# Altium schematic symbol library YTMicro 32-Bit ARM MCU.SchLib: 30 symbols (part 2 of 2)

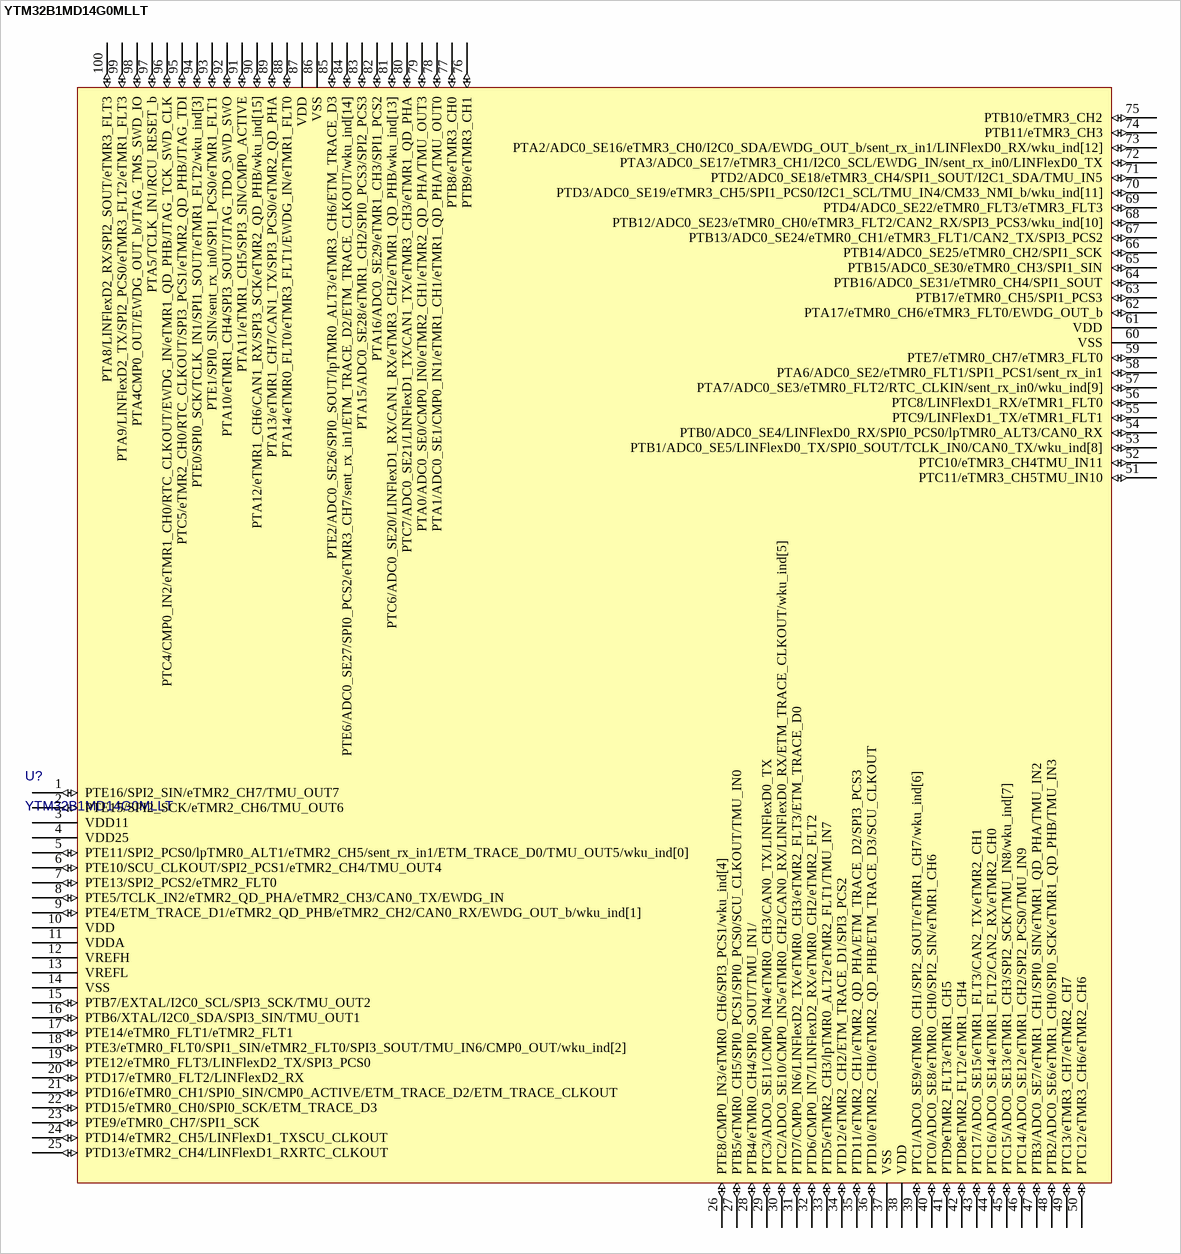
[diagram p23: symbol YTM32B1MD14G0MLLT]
## YTM32B1MD14G0MLLT
designator U?
B1M family  32-bit ARM Cortex-M33 MCU with 512K pflash and 64K SRAM, LQFP-100 package
footprint LQFP100 14x14_L
footprint LQFP100 14x14_M
footprint LQFP100 14x14_N
pins: 1 PTE16/SPI2_SIN/eTMR2_CH7/TMU_OUT7 (io), 2 PTE15/SPI2_SCK/eTMR2_CH6/TMU_OUT6 (io), 3 VDD11, 4 VDD25, 5 PTE11/SPI2_PCS0/lpTMR0_ALT1/eTMR2_CH5/sent_rx_in1/ETM_TRACE_D0/TMU_OUT5/wku_ind[0] (io), 6 PTE10/SCU_CLKOUT/SPI2_PCS1/eTMR2_CH4/TMU_OUT4 (io), 7 PTE13/SPI2_PCS2/eTMR2_FLT0 (io), 8 PTE5/TCLK_IN2/eTMR2_QD_PHA/eTMR2_CH3/CAN0_TX/EWDG_IN (io), 9 PTE4/ETM_TRACE_D1/eTMR2_QD_PHB/eTMR2_CH2/CAN0_RX/EWDG_OUT_b/wku_ind[1] (io), 10 VDD, 11 VDDA, 12 VREFH, 13 VREFL, 14 VSS, 15 PTB7/EXTAL/I2C0_SCL/SPI3_SCK/TMU_OUT2 (io), 16 PTB6/XTAL/I2C0_SDA/SPI3_SIN/TMU_OUT1 (io), 17 PTE14/eTMR0_FLT1/eTMR2_FLT1 (io), 18 PTE3/eTMR0_FLT0/SPI1_SIN/eTMR2_FLT0/SPI3_SOUT/TMU_IN6/CMP0_OUT/wku_ind[2] (io), 19 PTE12/eTMR0_FLT3/LINFlexD2_TX/SPI3_PCS0 (io), 20 PTD17/eTMR0_FLT2/LINFlexD2_RX (io), 21 PTD16/eTMR0_CH1/SPI0_SIN/CMP0_ACTIVE/ETM_TRACE_D2/ETM_TRACE_CLKOUT (io), 22 PTD15/eTMR0_CH0/SPI0_SCK/ETM_TRACE_D3 (io), 23 PTE9/eTMR0_CH7/SPI1_SCK (io), 24 PTD14/eTMR2_CH5/LINFlexD1_TXSCU_CLKOUT (io), 25 PTD13/eTMR2_CH4/LINFlexD1_RXRTC_CLKOUT (io), 26 PTE8/CMP0_IN3/eTMR0_CH6/SPI3_PCS1/wku_ind[4] (io), 27 PTB5/eTMR0_CH5/SPI0_PCS1/SPI0_PCS0/SCU_CLKOUT/TMU_IN0 (io), 28 PTB4/eTMR0_CH4/SPI0_SOUT/TMU_IN1/ (io), 29 PTC3/ADC0_SE11/CMP0_IN4/eTMR0_CH3/CAN0_TX/LINFlexD0_TX (io), 30 PTC2/ADC0_SE10/CMP0_IN5/eTMR0_CH2/CAN0_RX/LINFlexD0_RX/ETM_TRACE_CLKOUT/wku_ind[5] (io), 31 PTD7/CMP0_IN6/LINFlexD2_TX/eTMR0_CH3/eTMR2_FLT3/ETM_TRACE_D0 (io), 32 PTD6/CMP0_IN7/LINFlexD2_RX/eTMR0_CH2/eTMR2_FLT2 (io), 33 PTD5/eTMR2_CH3/lpTMR0_ALT2/eTMR2_FLT1/TMU_IN7 (io), 34 PTD12/eTMR2_CH2/ETM_TRACE_D1/SPI3_PCS2 (io), 35 PTD11/eTMR2_CH1/eTMR2_QD_PHA/ETM_TRACE_D2/SPI3_PCS3 (io), 36 PTD10/eTMR2_CH0/eTMR2_QD_PHB/ETM_TRACE_D3/SCU_CLKOUT (io), 37 VSS, 38 VDD, 39 PTC1/ADC0_SE9/eTMR0_CH1/SPI2_SOUT/eTMR1_CH7/wku_ind[6] (io), 40 PTC0/ADC0_SE8/eTMR0_CH0/SPI2_SIN/eTMR1_CH6 (io), 41 PTD9eTMR2_FLT3/eTMR1_CH5 (io), 42 PTD8eTMR2_FLT2/eTMR1_CH4 (io), 43 PTC17/ADC0_SE15/eTMR1_FLT3/CAN2_TX/eTMR2_CH1 (io), 44 PTC16/ADC0_SE14/eTMR1_FLT2/CAN2_RX/eTMR2_CH0 (io), 45 PTC15/ADC0_SE13/eTMR1_CH3/SPI2_SCK/TMU_IN8/wku_ind[7] (io), 46 PTC14/ADC0_SE12/eTMR1_CH2/SPI2_PCS0/TMU_IN9 (io), 47 PTB3/ADC0_SE7/eTMR1_CH1/SPI0_SIN/eTMR1_QD_PHA/TMU_IN2 (io), 48 PTB2/ADC0_SE6/eTMR1_CH0/SPI0_SCK/eTMR1_QD_PHB/TMU_IN3 (io), 49 PTC13/eTMR3_CH7/eTMR2_CH7 (io), 50 PTC12/eTMR3_CH6/eTMR2_CH6 (io), 51 PTC11/eTMR3_CH5TMU_IN10 (io), 52 PTC10/eTMR3_CH4TMU_IN11 (io), 53 PTB1/ADC0_SE5/LINFlexD0_TX/SPI0_SOUT/TCLK_IN0/CAN0_TX/wku_ind[8] (io), 54 PTB0/ADC0_SE4/LINFlexD0_RX/SPI0_PCS0/lpTMR0_ALT3/CAN0_RX (io), 55 PTC9/LINFlexD1_TX/eTMR1_FLT1 (io), 56 PTC8/LINFlexD1_RX/eTMR1_FLT0 (io), 57 PTA7/ADC0_SE3/eTMR0_FLT2/RTC_CLKIN/sent_rx_in0/wku_ind[9] (io), 58 PTA6/ADC0_SE2/eTMR0_FLT1/SPI1_PCS1/sent_rx_in1 (io), 59 PTE7/eTMR0_CH7/eTMR3_FLT0 (io), 60 VSS, 61 VDD, 62 PTA17/eTMR0_CH6/eTMR3_FLT0/EWDG_OUT_b (io), 63 PTB17/eTMR0_CH5/SPI1_PCS3 (io), 64 PTB16/ADC0_SE31/eTMR0_CH4/SPI1_SOUT (io), 65 PTB15/ADC0_SE30/eTMR0_CH3/SPI1_SIN (io), 66 PTB14/ADC0_SE25/eTMR0_CH2/SPI1_SCK (io), 67 PTB13/ADC0_SE24/eTMR0_CH1/eTMR3_FLT1/CAN2_TX/SPI3_PCS2 (io), 68 PTB12/ADC0_SE23/eTMR0_CH0/eTMR3_FLT2/CAN2_RX/SPI3_PCS3/wku_ind[10] (io), 69 PTD4/ADC0_SE22/eTMR0_FLT3/eTMR3_FLT3 (io), 70 PTD3/ADC0_SE19/eTMR3_CH5/SPI1_PCS0/I2C1_SCL/TMU_IN4/CM33_NMI_b/wku_ind[11] (io), 71 PTD2/ADC0_SE18/eTMR3_CH4/SPI1_SOUT/I2C1_SDA/TMU_IN5 (io), 72 PTA3/ADC0_SE17/eTMR3_CH1/I2C0_SCL/EWDG_IN/sent_rx_in0/LINFlexD0_TX (io), 73 PTA2/ADC0_SE16/eTMR3_CH0/I2C0_SDA/EWDG_OUT_b/sent_rx_in1/LINFlexD0_RX/wku_ind[12] (io), 74 PTB11/eTMR3_CH3 (io), 75 PTB10/eTMR3_CH2 (io), 76 PTB9/eTMR3_CH1 (io), 77 PTB8/eTMR3_CH0 (io), 78 PTA1/ADC0_SE1/CMP0_IN1/eTMR1_CH1/eTMR1_QD_PHA/TMU_OUT0 (io), 79 PTA0/ADC0_SE0/CMP0_IN0/eTMR2_CH1/eTMR2_QD_PHA/TMU_OUT3 (io), 80 PTC7/ADC0_SE21/LINFlexD1_TX/CAN1_TX/eTMR3_CH3/eTMR1_QD_PHA (io), 81 PTC6/ADC0_SE20/LINFlexD1_RX/CAN1_RX/eTMR3_CH2/eTMR1_QD_PHB/wku_ind[13] (io), 82 PTA16/ADC0_SE29/eTMR1_CH3/SPI1_PCS2 (io), 83 PTA15/ADC0_SE28/eTMR1_CH2/SPI0_PCS3/SPI2_PCS3 (io), 84 PTE6/ADC0_SE27/SPI0_PCS2/eTMR3_CH7/sent_rx_in1/ETM_TRACE_D2/ETM_TRACE_CLKOUT/wku_ind[14] (io), 85 PTE2/ADC0_SE26/SPI0_SOUT/lpTMR0_ALT3/eTMR3_CH6/ETM_TRACE_D3 (io), 86 VSS, 87 VDD, 88 PTA14/eTMR0_FLT0/eTMR3_FLT1/EWDG_IN/eTMR1_FLT0 (io), 89 PTA13/eTMR1_CH7/CAN1_TX/SPI3_PCS0/eTMR2_QD_PHA (io), 90 PTA12/eTMR1_CH6/CAN1_RX/SPI3_SCK/eTMR2_QD_PHB/wku_ind[15] (io), 91 PTA11/eTMR1_CH5/SPI3_SIN/CMP0_ACTIVE (io), 92 PTA10/eTMR1_CH4/SPI3_SOUT/JTAG_TDO_SWD_SWO (io), 93 PTE1/SPI0_SIN/sent_rx_in0/SPI1_PCS0/eTMR1_FLT1 (io), 94 PTE0/SPI0_SCK/TCLK_IN1/SPI1_SOUT/eTMR1_FLT2/wku_ind[3] (io), 95 PTC5/eTMR2_CH0/RTC_CLKOUT/SPI3_PCS1/eTMR2_QD_PHB/JTAG_TDI (io), 96 PTC4/CMP0_IN2/eTMR1_CH0/RTC_CLKOUT/EWDG_IN/eTMR1_QD_PHB/JTAG_TCK_SWD_CLK (io), 97 PTA5/TCLK_IN1/RCU_RESET_b (io), 98 PTA4CMP0_OUT/EWDG_OUT_b/JTAG_TMS_SWD_IO (io), 99 PTA9/LINFlexD2_TX/SPI2_PCS0/eTMR3_FLT2/eTMR1_FLT3 (io), 100 PTA8/LINFlexD2_RX/SPI2_SOUT/eTMR3_FLT3 (io)


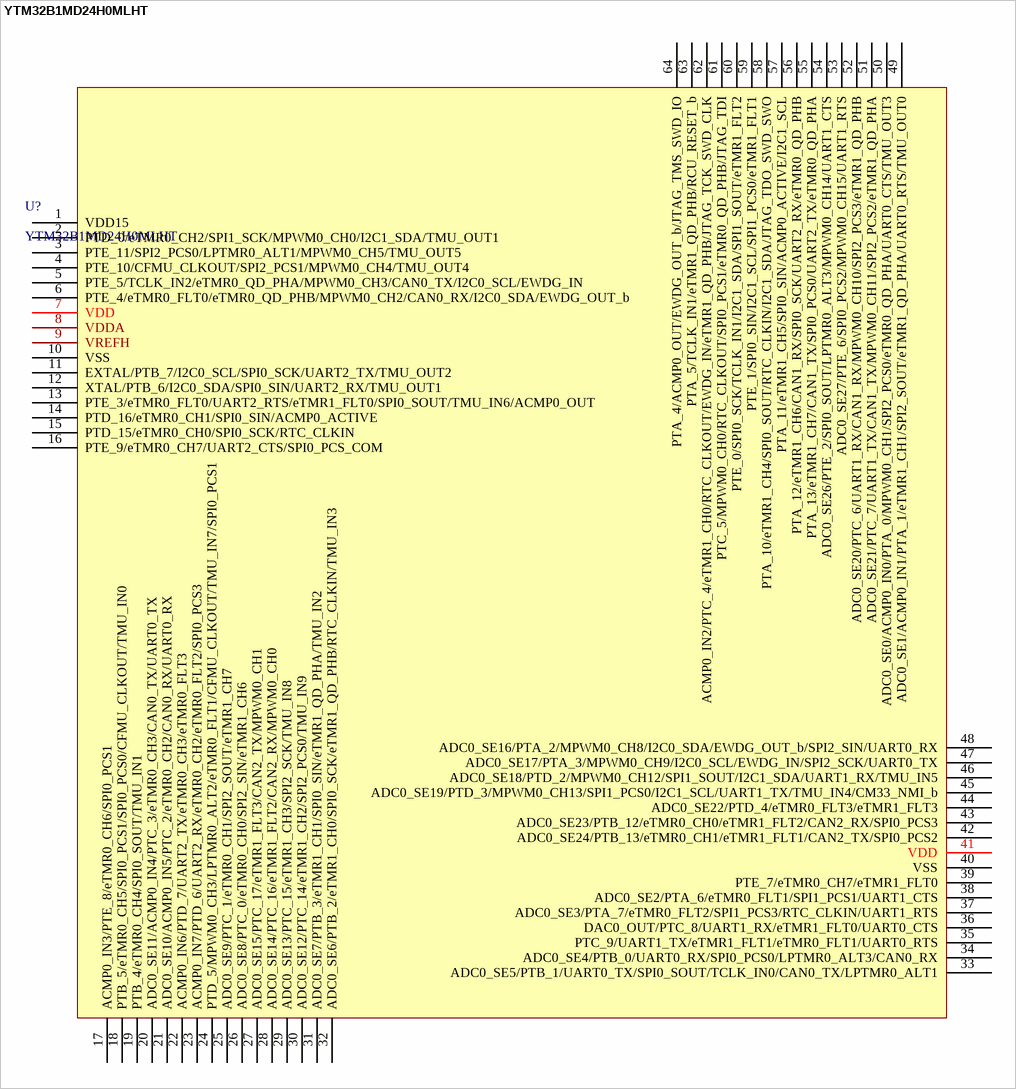
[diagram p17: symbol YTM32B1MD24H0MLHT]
## YTM32B1MD24H0MLHT
designator U?
B1M family  32-bit ARM Cortex-M33 MCU with 512K pflash and 64K SRAM, LQFP-64 package
footprint LQFP64 10x10_M
pins: 1 VDD15, 2 PTD_0/eTMR0_CH2/SPI1_SCK/MPWM0_CH0/I2C1_SDA/TMU_OUT1, 3 PTE_11/SPI2_PCS0/LPTMR0_ALT1/MPWM0_CH5/TMU_OUT5, 4 PTE_10/CFMU_CLKOUT/SPI2_PCS1/MPWM0_CH4/TMU_OUT4, 5 PTE_5/TCLK_IN2/eTMR0_QD_PHA/MPWM0_CH3/CAN0_TX/I2C0_SCL/EWDG_IN, 6 PTE_4/eTMR0_FLT0/eTMR0_QD_PHB/MPWM0_CH2/CAN0_RX/I2C0_SDA/EWDG_OUT_b, 7 VDD, 8 VDDA, 9 VREFH, 10 VSS, 11 EXTAL/PTB_7/I2C0_SCL/SPI0_SCK/UART2_TX/TMU_OUT2, 12 XTAL/PTB_6/I2C0_SDA/SPI0_SIN/UART2_RX/TMU_OUT1, 13 PTE_3/eTMR0_FLT0/UART2_RTS/eTMR1_FLT0/SPI0_SOUT/TMU_IN6/ACMP0_OUT, 14 PTD_16/eTMR0_CH1/SPI0_SIN/ACMP0_ACTIVE, 15 PTD_15/eTMR0_CH0/SPI0_SCK/RTC_CLKIN, 16 PTE_9/eTMR0_CH7/UART2_CTS/SPI0_PCS_COM, 17 ACMP0_IN3/PTE_8/eTMR0_CH6/SPI0_PCS1, 18 PTB_5/eTMR0_CH5/SPI0_PCS1/SPI0_PCS0/CFMU_CLKOUT/TMU_IN0, 19 PTB_4/eTMR0_CH4/SPI0_SOUT/TMU_IN1, 20 ADC0_SE11/ACMP0_IN4/PTC_3/eTMR0_CH3/CAN0_TX/UART0_TX, 21 ADC0_SE10/ACMP0_IN5/PTC_2/eTMR0_CH2/CAN0_RX/UART0_RX, 22 ACMP0_IN6/PTD_7/UART2_TX/eTMR0_CH3/eTMR0_FLT3, 23 ACMP0_IN7/PTD_6/UART2_RX/eTMR0_CH2/eTMR0_FLT2/SPI0_PCS3, 24 PTD_5/MPWM0_CH3/LPTMR0_ALT2/eTMR0_FLT1/CFMU_CLKOUT/TMU_IN7/SPI0_PCS1, 25 ADC0_SE9/PTC_1/eTMR0_CH1/SPI2_SOUT/eTMR1_CH7, 26 ADC0_SE8/PTC_0/eTMR0_CH0/SPI2_SIN/eTMR1_CH6, 27 ADC0_SE15/PTC_17/eTMR1_FLT3/CAN2_TX/MPWM0_CH1, 28 ADC0_SE14/PTC_16/eTMR1_FLT2/CAN2_RX/MPWM0_CH0, 29 ADC0_SE13/PTC_15/eTMR1_CH3/SPI2_SCK/TMU_IN8, 30 ADC0_SE12/PTC_14/eTMR1_CH2/SPI2_PCS0/TMU_IN9, 31 ADC0_SE7/PTB_3/eTMR1_CH1/SPI0_SIN/eTMR1_QD_PHA/TMU_IN2, 32 ADC0_SE6/PTB_2/eTMR1_CH0/SPI0_SCK/eTMR1_QD_PHB/RTC_CLKIN/TMU_IN3, 33 ADC0_SE5/PTB_1/UART0_TX/SPI0_SOUT/TCLK_IN0/CAN0_TX/LPTMR0_ALT1, 34 ADC0_SE4/PTB_0/UART0_RX/SPI0_PCS0/LPTMR0_ALT3/CAN0_RX, 35 PTC_9/UART1_TX/eTMR1_FLT1/eTMR0_FLT1/UART0_RTS, 36 DAC0_OUT/PTC_8/UART1_RX/eTMR1_FLT0/UART0_CTS, 37 ADC0_SE3/PTA_7/eTMR0_FLT2/SPI1_PCS3/RTC_CLKIN/UART1_RTS, 38 ADC0_SE2/PTA_6/eTMR0_FLT1/SPI1_PCS1/UART1_CTS, 39 PTE_7/eTMR0_CH7/eTMR1_FLT0, 40 VSS, 41 VDD, 42 ADC0_SE24/PTB_13/eTMR0_CH1/eTMR1_FLT1/CAN2_TX/SPI0_PCS2, 43 ADC0_SE23/PTB_12/eTMR0_CH0/eTMR1_FLT2/CAN2_RX/SPI0_PCS3, 44 ADC0_SE22/PTD_4/eTMR0_FLT3/eTMR1_FLT3, 45 ADC0_SE19/PTD_3/MPWM0_CH13/SPI1_PCS0/I2C1_SCL/UART1_TX/TMU_IN4/CM33_NMI_b, 46 ADC0_SE18/PTD_2/MPWM0_CH12/SPI1_SOUT/I2C1_SDA/UART1_RX/TMU_IN5, 47 ADC0_SE17/PTA_3/MPWM0_CH9/I2C0_SCL/EWDG_IN/SPI2_SCK/UART0_TX, 48 ADC0_SE16/PTA_2/MPWM0_CH8/I2C0_SDA/EWDG_OUT_b/SPI2_SIN/UART0_RX, 49 ADC0_SE1/ACMP0_IN1/PTA_1/eTMR1_CH1/SPI2_SOUT/eTMR1_QD_PHA/UART0_RTS/TMU_OUT0, 50 ADC0_SE0/ACMP0_IN0/PTA_0/MPWM0_CH1/SPI2_PCS0/eTMR0_QD_PHA/UART0_CTS/TMU_OUT3, 51 ADC0_SE21/PTC_7/UART1_TX/CAN1_TX/MPWM0_CH11/SPI2_PCS2/eTMR1_QD_PHA, 52 ADC0_SE20/PTC_6/UART1_RX/CAN1_RX/MPWM0_CH10/SPI2_PCS3/eTMR1_QD_PHB, 53 ADC0_SE27/PTE_6/SPI0_PCS2/MPWM0_CH15/UART1_RTS, 54 ADC0_SE26/PTE_2/SPI0_SOUT/LPTMR0_ALT3/MPWM0_CH14/UART1_CTS, 55 PTA_13/eTMR1_CH7/CAN1_TX/SPI0_PCS0/UART2_TX/eTMR0_QD_PHA, 56 PTA_12/eTMR1_CH6/CAN1_RX/SPI0_SCK/UART2_RX/eTMR0_QD_PHB, 57 PTA_11/eTMR1_CH5/SPI0_SIN/ACMP0_ACTIVE/I2C1_SCL, 58 PTA_10/eTMR1_CH4/SPI0_SOUT/RTC_CLKIN/I2C1_SDA/JTAG_TDO_SWD_SWO, 59 PTE_1/SPI0_SIN/I2C1_SCL/SPI1_PCS0/eTMR1_FLT1, 60 PTE_0/SPI0_SCK/TCLK_IN1/I2C1_SDA/SPI1_SOUT/eTMR1_FLT2, 61 PTC_5/MPWM0_CH0/RTC_CLKOUT/SPI0_PCS1/eTMR0_QD_PHB/JTAG_TDI, 62 ACMP0_IN2/PTC_4/eTMR1_CH0/RTC_CLKOUT/EWDG_IN/eTMR1_QD_PHB/JTAG_TCK_SWD_CLK, 63 PTA_5/TCLK_IN1/eTMR1_QD_PHB/RCU_RESET_b, 64 PTA_4/ACMP0_OUT/EWDG_OUT_b/JTAG_TMS_SWD_IO


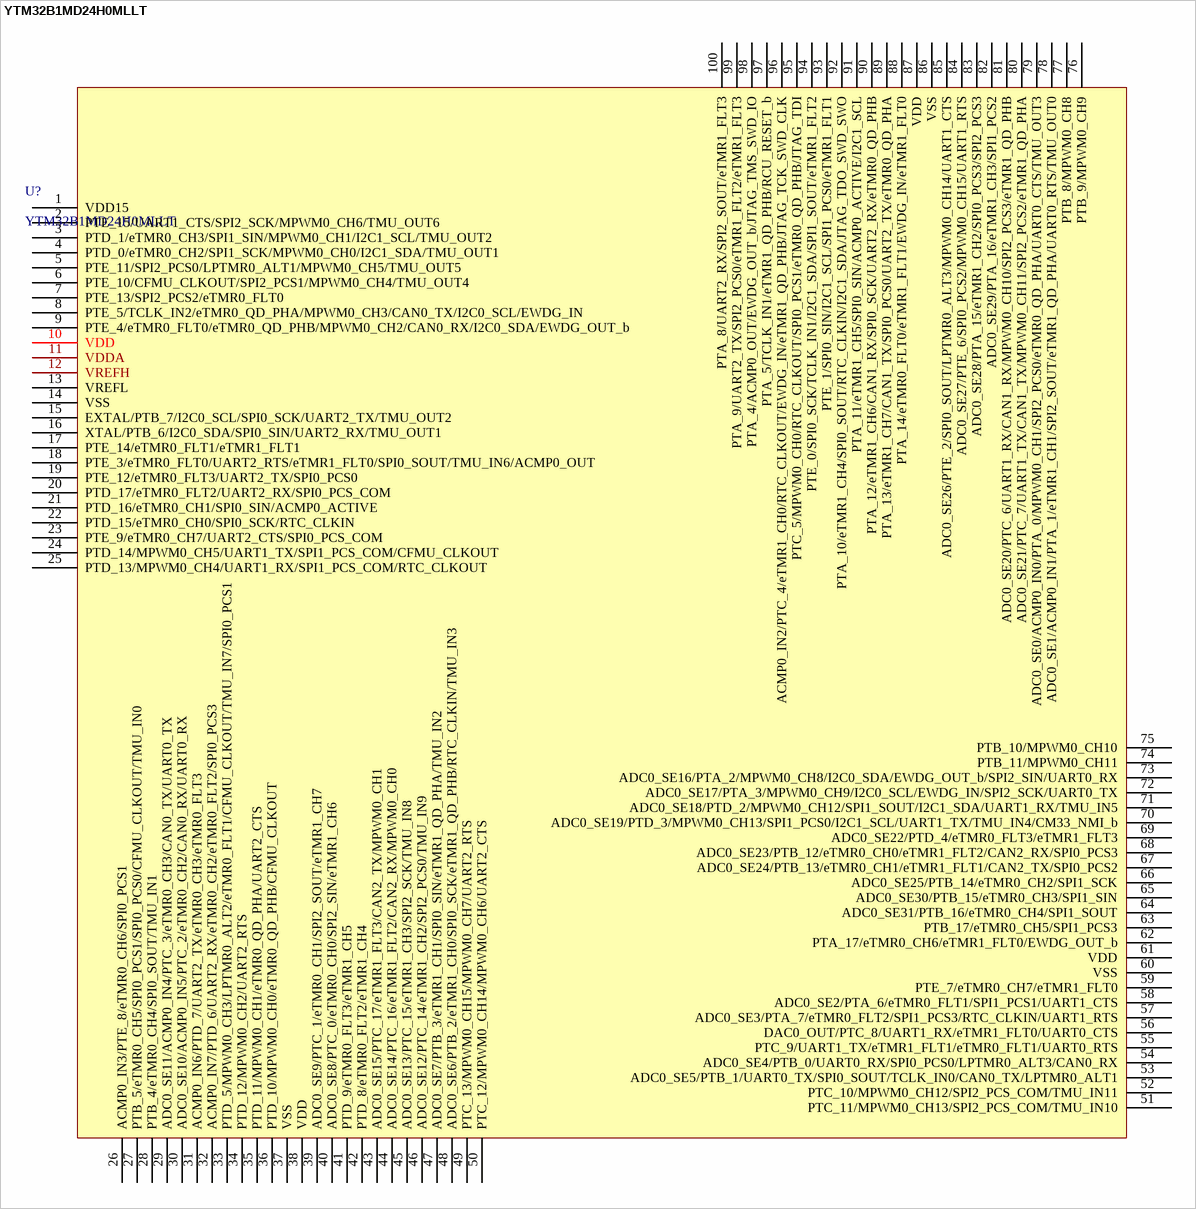
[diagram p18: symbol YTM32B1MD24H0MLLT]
## YTM32B1MD24H0MLLT
designator U?
B1M family  32-bit ARM Cortex-M33 MCU with 512K pflash and 64K SRAM, LQFP-100 package
footprint LQFP100 14x14_M
pins: 1 VDD15, 2 PTE_15/UART1_CTS/SPI2_SCK/MPWM0_CH6/TMU_OUT6, 3 PTD_1/eTMR0_CH3/SPI1_SIN/MPWM0_CH1/I2C1_SCL/TMU_OUT2, 4 PTD_0/eTMR0_CH2/SPI1_SCK/MPWM0_CH0/I2C1_SDA/TMU_OUT1, 5 PTE_11/SPI2_PCS0/LPTMR0_ALT1/MPWM0_CH5/TMU_OUT5, 6 PTE_10/CFMU_CLKOUT/SPI2_PCS1/MPWM0_CH4/TMU_OUT4, 7 PTE_13/SPI2_PCS2/eTMR0_FLT0, 8 PTE_5/TCLK_IN2/eTMR0_QD_PHA/MPWM0_CH3/CAN0_TX/I2C0_SCL/EWDG_IN, 9 PTE_4/eTMR0_FLT0/eTMR0_QD_PHB/MPWM0_CH2/CAN0_RX/I2C0_SDA/EWDG_OUT_b, 10 VDD, 11 VDDA, 12 VREFH, 13 VREFL, 14 VSS, 15 EXTAL/PTB_7/I2C0_SCL/SPI0_SCK/UART2_TX/TMU_OUT2, 16 XTAL/PTB_6/I2C0_SDA/SPI0_SIN/UART2_RX/TMU_OUT1, 17 PTE_14/eTMR0_FLT1/eTMR1_FLT1, 18 PTE_3/eTMR0_FLT0/UART2_RTS/eTMR1_FLT0/SPI0_SOUT/TMU_IN6/ACMP0_OUT, 19 PTE_12/eTMR0_FLT3/UART2_TX/SPI0_PCS0, 20 PTD_17/eTMR0_FLT2/UART2_RX/SPI0_PCS_COM, 21 PTD_16/eTMR0_CH1/SPI0_SIN/ACMP0_ACTIVE, 22 PTD_15/eTMR0_CH0/SPI0_SCK/RTC_CLKIN, 23 PTE_9/eTMR0_CH7/UART2_CTS/SPI0_PCS_COM, 24 PTD_14/MPWM0_CH5/UART1_TX/SPI1_PCS_COM/CFMU_CLKOUT, 25 PTD_13/MPWM0_CH4/UART1_RX/SPI1_PCS_COM/RTC_CLKOUT, 26 ACMP0_IN3/PTE_8/eTMR0_CH6/SPI0_PCS1, 27 PTB_5/eTMR0_CH5/SPI0_PCS1/SPI0_PCS0/CFMU_CLKOUT/TMU_IN0, 28 PTB_4/eTMR0_CH4/SPI0_SOUT/TMU_IN1, 29 ADC0_SE11/ACMP0_IN4/PTC_3/eTMR0_CH3/CAN0_TX/UART0_TX, 30 ADC0_SE10/ACMP0_IN5/PTC_2/eTMR0_CH2/CAN0_RX/UART0_RX, 31 ACMP0_IN6/PTD_7/UART2_TX/eTMR0_CH3/eTMR0_FLT3, 32 ACMP0_IN7/PTD_6/UART2_RX/eTMR0_CH2/eTMR0_FLT2/SPI0_PCS3, 33 PTD_5/MPWM0_CH3/LPTMR0_ALT2/eTMR0_FLT1/CFMU_CLKOUT/TMU_IN7/SPI0_PCS1, 34 PTD_12/MPWM0_CH2/UART2_RTS, 35 PTD_11/MPWM0_CH1/eTMR0_QD_PHA/UART2_CTS, 36 PTD_10/MPWM0_CH0/eTMR0_QD_PHB/CFMU_CLKOUT, 37 VSS, 38 VDD, 39 ADC0_SE9/PTC_1/eTMR0_CH1/SPI2_SOUT/eTMR1_CH7, 40 ADC0_SE8/PTC_0/eTMR0_CH0/SPI2_SIN/eTMR1_CH6, 41 PTD_9/eTMR0_FLT3/eTMR1_CH5, 42 PTD_8/eTMR0_FLT2/eTMR1_CH4, 43 ADC0_SE15/PTC_17/eTMR1_FLT3/CAN2_TX/MPWM0_CH1, 44 ADC0_SE14/PTC_16/eTMR1_FLT2/CAN2_RX/MPWM0_CH0, 45 ADC0_SE13/PTC_15/eTMR1_CH3/SPI2_SCK/TMU_IN8, 46 ADC0_SE12/PTC_14/eTMR1_CH2/SPI2_PCS0/TMU_IN9, 47 ADC0_SE7/PTB_3/eTMR1_CH1/SPI0_SIN/eTMR1_QD_PHA/TMU_IN2, 48 ADC0_SE6/PTB_2/eTMR1_CH0/SPI0_SCK/eTMR1_QD_PHB/RTC_CLKIN/TMU_IN3, 49 PTC_13/MPWM0_CH15/MPWM0_CH7/UART2_RTS, 50 PTC_12/MPWM0_CH14/MPWM0_CH6/UART2_CTS, 51 PTC_11/MPWM0_CH13/SPI2_PCS_COM/TMU_IN10, 52 PTC_10/MPWM0_CH12/SPI2_PCS_COM/TMU_IN11, 53 ADC0_SE5/PTB_1/UART0_TX/SPI0_SOUT/TCLK_IN0/CAN0_TX/LPTMR0_ALT1, 54 ADC0_SE4/PTB_0/UART0_RX/SPI0_PCS0/LPTMR0_ALT3/CAN0_RX, 55 PTC_9/UART1_TX/eTMR1_FLT1/eTMR0_FLT1/UART0_RTS, 56 DAC0_OUT/PTC_8/UART1_RX/eTMR1_FLT0/UART0_CTS, 57 ADC0_SE3/PTA_7/eTMR0_FLT2/SPI1_PCS3/RTC_CLKIN/UART1_RTS, 58 ADC0_SE2/PTA_6/eTMR0_FLT1/SPI1_PCS1/UART1_CTS, 59 PTE_7/eTMR0_CH7/eTMR1_FLT0, 60 VSS, 61 VDD, 62 PTA_17/eTMR0_CH6/eTMR1_FLT0/EWDG_OUT_b, 63 PTB_17/eTMR0_CH5/SPI1_PCS3, 64 ADC0_SE31/PTB_16/eTMR0_CH4/SPI1_SOUT, 65 ADC0_SE30/PTB_15/eTMR0_CH3/SPI1_SIN, 66 ADC0_SE25/PTB_14/eTMR0_CH2/SPI1_SCK, 67 ADC0_SE24/PTB_13/eTMR0_CH1/eTMR1_FLT1/CAN2_TX/SPI0_PCS2, 68 ADC0_SE23/PTB_12/eTMR0_CH0/eTMR1_FLT2/CAN2_RX/SPI0_PCS3, 69 ADC0_SE22/PTD_4/eTMR0_FLT3/eTMR1_FLT3, 70 ADC0_SE19/PTD_3/MPWM0_CH13/SPI1_PCS0/I2C1_SCL/UART1_TX/TMU_IN4/CM33_NMI_b, 71 ADC0_SE18/PTD_2/MPWM0_CH12/SPI1_SOUT/I2C1_SDA/UART1_RX/TMU_IN5, 72 ADC0_SE17/PTA_3/MPWM0_CH9/I2C0_SCL/EWDG_IN/SPI2_SCK/UART0_TX, 73 ADC0_SE16/PTA_2/MPWM0_CH8/I2C0_SDA/EWDG_OUT_b/SPI2_SIN/UART0_RX, 74 PTB_11/MPWM0_CH11, 75 PTB_10/MPWM0_CH10, 76 PTB_9/MPWM0_CH9, 77 PTB_8/MPWM0_CH8, 78 ADC0_SE1/ACMP0_IN1/PTA_1/eTMR1_CH1/SPI2_SOUT/eTMR1_QD_PHA/UART0_RTS/TMU_OUT0, 79 ADC0_SE0/ACMP0_IN0/PTA_0/MPWM0_CH1/SPI2_PCS0/eTMR0_QD_PHA/UART0_CTS/TMU_OUT3, 80 ADC0_SE21/PTC_7/UART1_TX/CAN1_TX/MPWM0_CH11/SPI2_PCS2/eTMR1_QD_PHA, 81 ADC0_SE20/PTC_6/UART1_RX/CAN1_RX/MPWM0_CH10/SPI2_PCS3/eTMR1_QD_PHB, 82 ADC0_SE29/PTA_16/eTMR1_CH3/SPI1_PCS2, 83 ADC0_SE28/PTA_15/eTMR1_CH2/SPI0_PCS3/SPI2_PCS3, 84 ADC0_SE27/PTE_6/SPI0_PCS2/MPWM0_CH15/UART1_RTS, 85 ADC0_SE26/PTE_2/SPI0_SOUT/LPTMR0_ALT3/MPWM0_CH14/UART1_CTS, 86 VSS, 87 VDD, 88 PTA_14/eTMR0_FLT0/eTMR1_FLT1/EWDG_IN/eTMR1_FLT0, 89 PTA_13/eTMR1_CH7/CAN1_TX/SPI0_PCS0/UART2_TX/eTMR0_QD_PHA, 90 PTA_12/eTMR1_CH6/CAN1_RX/SPI0_SCK/UART2_RX/eTMR0_QD_PHB, 91 PTA_11/eTMR1_CH5/SPI0_SIN/ACMP0_ACTIVE/I2C1_SCL, 92 PTA_10/eTMR1_CH4/SPI0_SOUT/RTC_CLKIN/I2C1_SDA/JTAG_TDO_SWD_SWO, 93 PTE_1/SPI0_SIN/I2C1_SCL/SPI1_PCS0/eTMR1_FLT1, 94 PTE_0/SPI0_SCK/TCLK_IN1/I2C1_SDA/SPI1_SOUT/eTMR1_FLT2, 95 PTC_5/MPWM0_CH0/RTC_CLKOUT/SPI0_PCS1/eTMR0_QD_PHB/JTAG_TDI, 96 ACMP0_IN2/PTC_4/eTMR1_CH0/RTC_CLKOUT/EWDG_IN/eTMR1_QD_PHB/JTAG_TCK_SWD_CLK, 97 PTA_5/TCLK_IN1/eTMR1_QD_PHB/RCU_RESET_b, 98 PTA_4/ACMP0_OUT/EWDG_OUT_b/JTAG_TMS_SWD_IO, 99 PTA_9/UART2_TX/SPI2_PCS0/eTMR1_FLT2/eTMR1_FLT3, 100 PTA_8/UART2_RX/SPI2_SOUT/eTMR1_FLT3


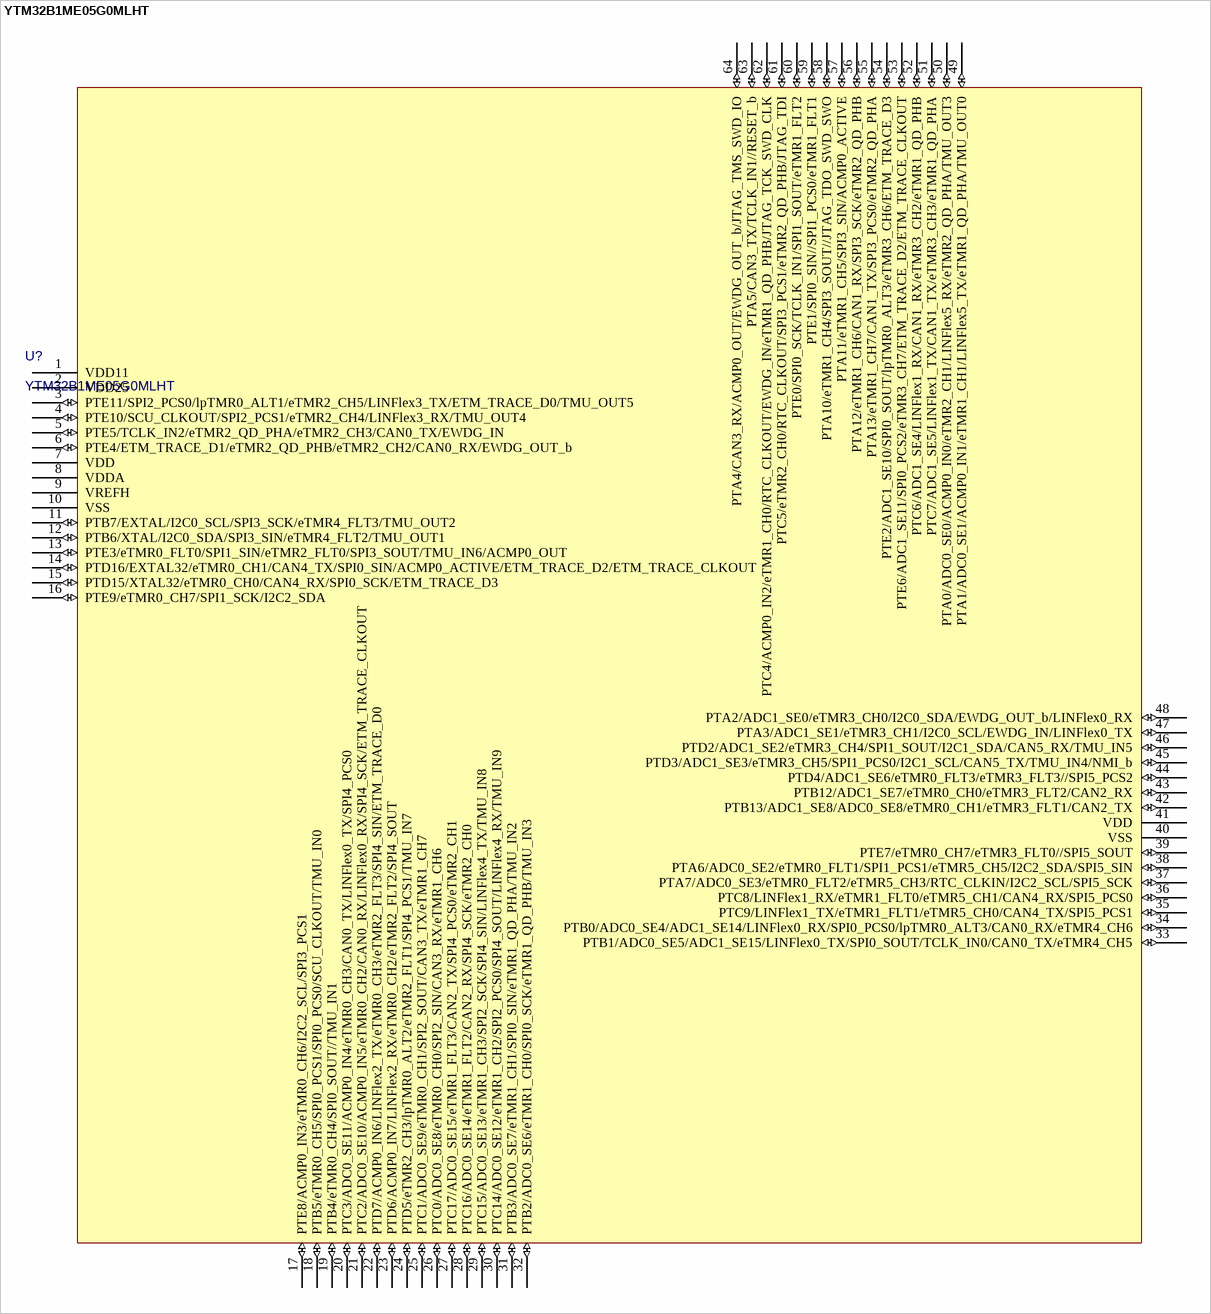
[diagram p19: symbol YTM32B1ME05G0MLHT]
## YTM32B1ME05G0MLHT
designator U?
B1M family  32-bit ARM Cortex-M33 MCU with 1M pflash, 256K dflash and 128K SRAM, LQFP-64 package
footprint LQFP64 10x10_L
footprint LQFP64 10x10_M
footprint LQFP64 10x10_N
pins: 1 VDD11, 2 VDD25, 3 PTE11/SPI2_PCS0/lpTMR0_ALT1/eTMR2_CH5/LINFlex3_TX/ETM_TRACE_D0/TMU_OUT5 (io), 4 PTE10/SCU_CLKOUT/SPI2_PCS1/eTMR2_CH4/LINFlex3_RX/TMU_OUT4 (io), 5 PTE5/TCLK_IN2/eTMR2_QD_PHA/eTMR2_CH3/CAN0_TX/EWDG_IN (io), 6 PTE4/ETM_TRACE_D1/eTMR2_QD_PHB/eTMR2_CH2/CAN0_RX/EWDG_OUT_b (io), 7 VDD, 8 VDDA, 9 VREFH, 10 VSS, 11 PTB7/EXTAL/I2C0_SCL/SPI3_SCK/eTMR4_FLT3/TMU_OUT2 (io), 12 PTB6/XTAL/I2C0_SDA/SPI3_SIN/eTMR4_FLT2/TMU_OUT1 (io), 13 PTE3/eTMR0_FLT0/SPI1_SIN/eTMR2_FLT0/SPI3_SOUT/TMU_IN6/ACMP0_OUT (io), 14 PTD16/EXTAL32/eTMR0_CH1/CAN4_TX/SPI0_SIN/ACMP0_ACTIVE/ETM_TRACE_D2/ETM_TRACE_CLKOUT (io), 15 PTD15/XTAL32/eTMR0_CH0/CAN4_RX/SPI0_SCK/ETM_TRACE_D3 (io), 16 PTE9/eTMR0_CH7/SPI1_SCK/I2C2_SDA (io), 17 PTE8/ACMP0_IN3/eTMR0_CH6/I2C2_SCL/SPI3_PCS1 (io), 18 PTB5/eTMR0_CH5/SPI0_PCS1/SPI0_PCS0/SCU_CLKOUT/TMU_IN0 (io), 19 PTB4/eTMR0_CH4/SPI0_SOUT//TMU_IN1 (io), 20 PTC3/ADC0_SE11/ACMP0_IN4/eTMR0_CH3/CAN0_TX/LINFlex0_TX/SPI4_PCS0 (io), 21 PTC2/ADC0_SE10/ACMP0_IN5/eTMR0_CH2/CAN0_RX/LINFlex0_RX/SPI4_SCK/ETM_TRACE_CLKOUT (io), 22 PTD7/ACMP0_IN6/LINFlex2_TX/eTMR0_CH3/eTMR2_FLT3/SPI4_SIN/ETM_TRACE_D0 (io), 23 PTD6/ACMP0_IN7/LINFlex2_RX/eTMR0_CH2/eTMR2_FLT2/SPI4_SOUT (io), 24 PTD5/eTMR2_CH3/lpTMR0_ALT2/eTMR2_FLT1/SPI4_PCS1/TMU_IN7 (io), 25 PTC1/ADC0_SE9/eTMR0_CH1/SPI2_SOUT/CAN3_TX/eTMR1_CH7 (io), 26 PTC0/ADC0_SE8/eTMR0_CH0/SPI2_SIN/CAN3_RX/eTMR1_CH6 (io), 27 PTC17/ADC0_SE15/eTMR1_FLT3/CAN2_TX/SPI4_PCS0/eTMR2_CH1 (io), 28 PTC16/ADC0_SE14/eTMR1_FLT2/CAN2_RX/SPI4_SCK/eTMR2_CH0 (io), 29 PTC15/ADC0_SE13/eTMR1_CH3/SPI2_SCK/SPI4_SIN/LINFlex4_TX/TMU_IN8 (io), 30 PTC14/ADC0_SE12/eTMR1_CH2/SPI2_PCS0/SPI4_SOUT/LINFlex4_RX/TMU_IN9 (io), 31 PTB3/ADC0_SE7/eTMR1_CH1/SPI0_SIN/eTMR1_QD_PHA/TMU_IN2 (io), 32 PTB2/ADC0_SE6/eTMR1_CH0/SPI0_SCK/eTMR1_QD_PHB/TMU_IN3 (io), 33 PTB1/ADC0_SE5/ADC1_SE15/LINFlex0_TX/SPI0_SOUT/TCLK_IN0/CAN0_TX/eTMR4_CH5 (io), 34 PTB0/ADC0_SE4/ADC1_SE14/LINFlex0_RX/SPI0_PCS0/lpTMR0_ALT3/CAN0_RX/eTMR4_CH6 (io), 35 PTC9/LINFlex1_TX/eTMR1_FLT1/eTMR5_CH0/CAN4_TX/SPI5_PCS1 (io), 36 PTC8/LINFlex1_RX/eTMR1_FLT0/eTMR5_CH1/CAN4_RX/SPI5_PCS0 (io), 37 PTA7/ADC0_SE3/eTMR0_FLT2/eTMR5_CH3/RTC_CLKIN/I2C2_SCL/SPI5_SCK (io), 38 PTA6/ADC0_SE2/eTMR0_FLT1/SPI1_PCS1/eTMR5_CH5/I2C2_SDA/SPI5_SIN (io), 39 PTE7/eTMR0_CH7/eTMR3_FLT0//SPI5_SOUT (io), 40 VSS, 41 VDD, 42 PTB13/ADC1_SE8/ADC0_SE8/eTMR0_CH1/eTMR3_FLT1/CAN2_TX (io), 43 PTB12/ADC1_SE7/eTMR0_CH0/eTMR3_FLT2/CAN2_RX (io), 44 PTD4/ADC1_SE6/eTMR0_FLT3/eTMR3_FLT3//SPI5_PCS2 (io), 45 PTD3/ADC1_SE3/eTMR3_CH5/SPI1_PCS0/I2C1_SCL/CAN5_TX/TMU_IN4/NMI_b (io), 46 PTD2/ADC1_SE2/eTMR3_CH4/SPI1_SOUT/I2C1_SDA/CAN5_RX/TMU_IN5 (io), 47 PTA3/ADC1_SE1/eTMR3_CH1/I2C0_SCL/EWDG_IN/LINFlex0_TX (io), 48 PTA2/ADC1_SE0/eTMR3_CH0/I2C0_SDA/EWDG_OUT_b/LINFlex0_RX (io), 49 PTA1/ADC0_SE1/ACMP0_IN1/eTMR1_CH1/LINFlex5_TX/eTMR1_QD_PHA/TMU_OUT0 (io), 50 PTA0/ADC0_SE0/ACMP0_IN0/eTMR2_CH1/LINFlex5_RX/eTMR2_QD_PHA/TMU_OUT3 (io), 51 PTC7/ADC1_SE5/LINFlex1_TX/CAN1_TX/eTMR3_CH3/eTMR1_QD_PHA (io), 52 PTC6/ADC1_SE4/LINFlex1_RX/CAN1_RX/eTMR3_CH2/eTMR1_QD_PHB (io), 53 PTE6/ADC1_SE11/SPI0_PCS2/eTMR3_CH7/ETM_TRACE_D2/ETM_TRACE_CLKOUT (io), 54 PTE2/ADC1_SE10/SPI0_SOUT/lpTMR0_ALT3/eTMR3_CH6/ETM_TRACE_D3 (io), 55 PTA13/eTMR1_CH7/CAN1_TX/SPI3_PCS0/eTMR2_QD_PHA (io), 56 PTA12/eTMR1_CH6/CAN1_RX/SPI3_SCK/eTMR2_QD_PHB (io), 57 PTA11/eTMR1_CH5/SPI3_SIN/ACMP0_ACTIVE (io), 58 PTA10/eTMR1_CH4/SPI3_SOUT//JTAG_TDO_SWD_SWO (io), 59 PTE1/SPI0_SIN//SPI1_PCS0/eTMR1_FLT1 (io), 60 PTE0/SPI0_SCK/TCLK_IN1/SPI1_SOUT/eTMR1_FLT2 (io), 61 PTC5/eTMR2_CH0/RTC_CLKOUT/SPI3_PCS1/eTMR2_QD_PHB/JTAG_TDI (io), 62 PTC4/ACMP0_IN2/eTMR1_CH0/RTC_CLKOUT/EWDG_IN/eTMR1_QD_PHB/JTAG_TCK_SWD_CLK (io), 63 PTA5/CAN3_TX/TCLK_IN1//RESET_b (io), 64 PTA4/CAN3_RX/ACMP0_OUT/EWDG_OUT_b/JTAG_TMS_SWD_IO (io)


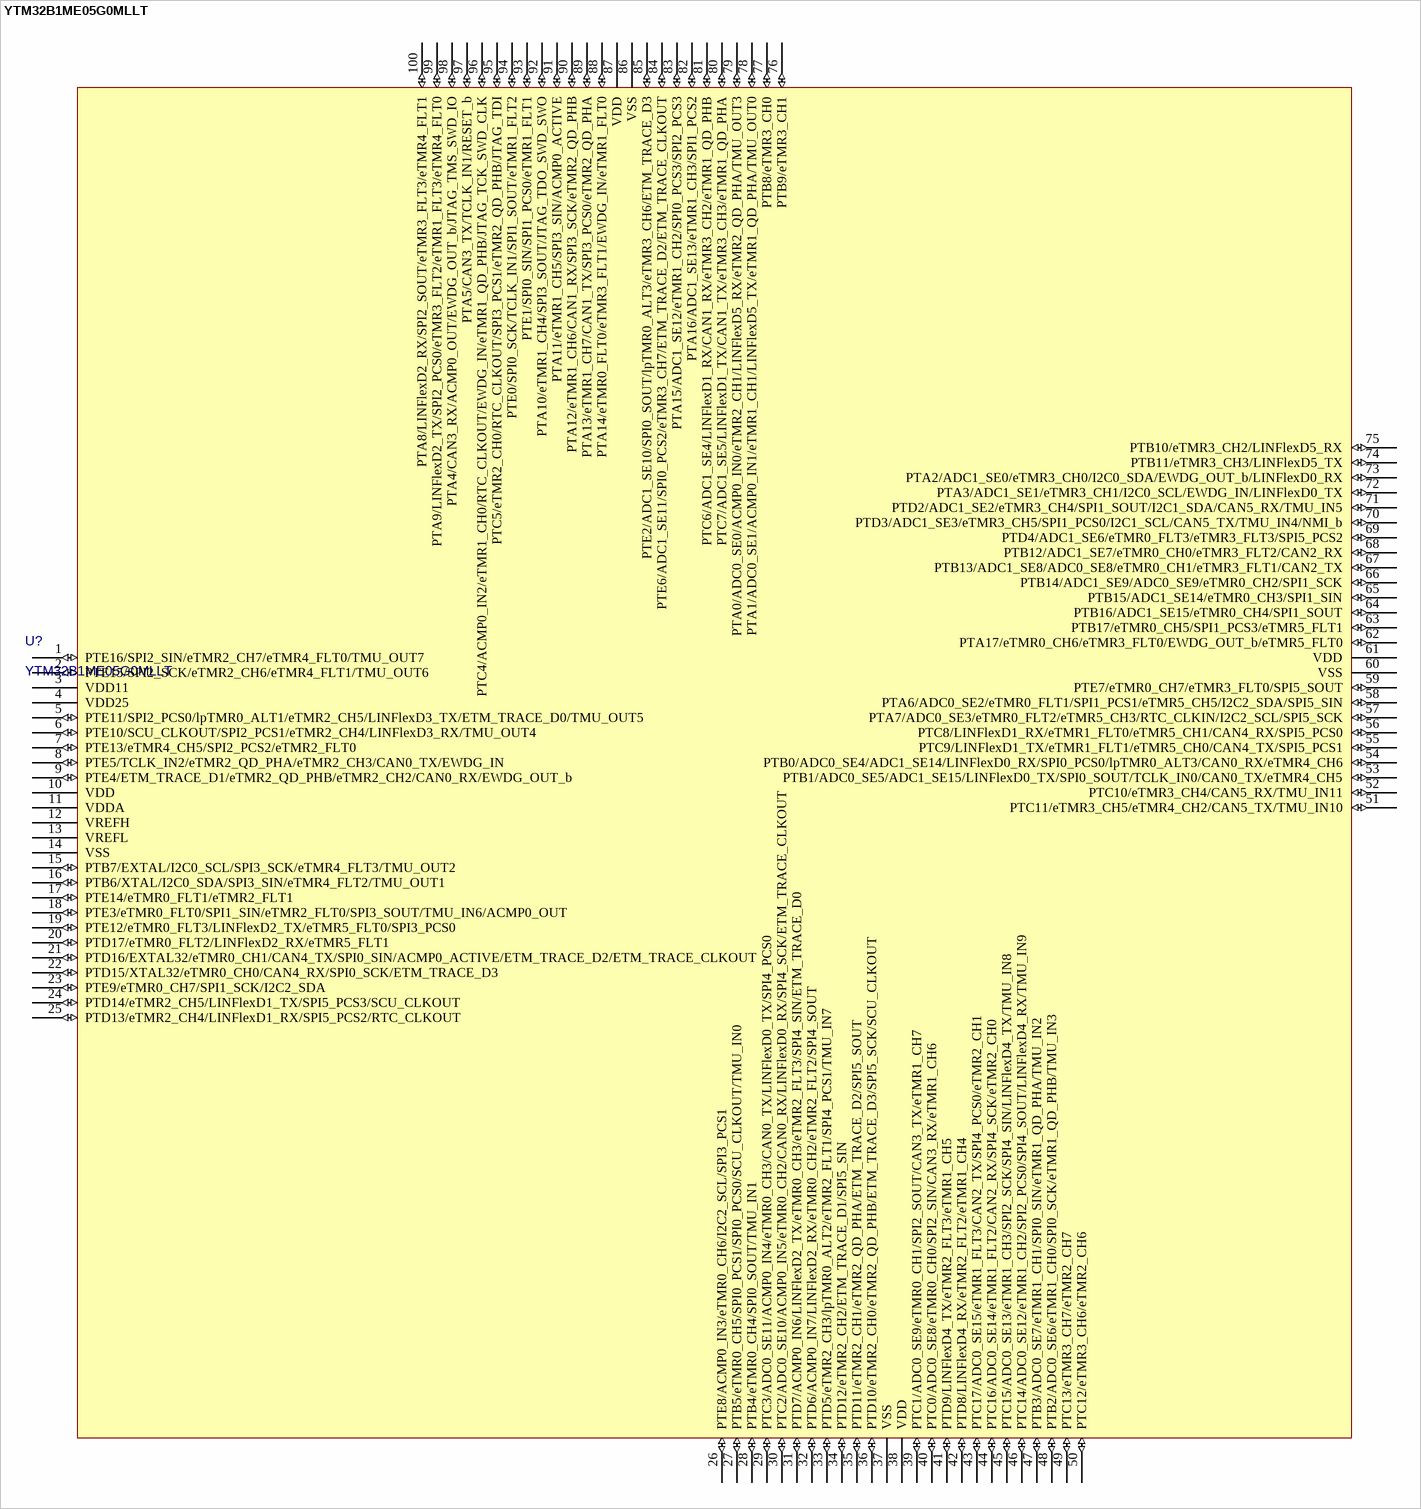
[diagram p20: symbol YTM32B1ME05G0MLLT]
## YTM32B1ME05G0MLLT
designator U?
B1M family  32-bit ARM Cortex-M33 MCU with 1M pflash, 256K dflash and 128K SRAM, LQFP-100 package
footprint LQFP100 14x14_L
footprint LQFP100 14x14_M
footprint LQFP100 14x14_N
pins: 1 PTE16/SPI2_SIN/eTMR2_CH7/eTMR4_FLT0/TMU_OUT7 (io), 2 PTE15/SPI2_SCK/eTMR2_CH6/eTMR4_FLT1/TMU_OUT6 (io), 3 VDD11, 4 VDD25, 5 PTE11/SPI2_PCS0/lpTMR0_ALT1/eTMR2_CH5/LINFlexD3_TX/ETM_TRACE_D0/TMU_OUT5 (io), 6 PTE10/SCU_CLKOUT/SPI2_PCS1/eTMR2_CH4/LINFlexD3_RX/TMU_OUT4 (io), 7 PTE13/eTMR4_CH5/SPI2_PCS2/eTMR2_FLT0 (io), 8 PTE5/TCLK_IN2/eTMR2_QD_PHA/eTMR2_CH3/CAN0_TX/EWDG_IN (io), 9 PTE4/ETM_TRACE_D1/eTMR2_QD_PHB/eTMR2_CH2/CAN0_RX/EWDG_OUT_b (io), 10 VDD, 11 VDDA, 12 VREFH, 13 VREFL, 14 VSS, 15 PTB7/EXTAL/I2C0_SCL/SPI3_SCK/eTMR4_FLT3/TMU_OUT2 (io), 16 PTB6/XTAL/I2C0_SDA/SPI3_SIN/eTMR4_FLT2/TMU_OUT1 (io), 17 PTE14/eTMR0_FLT1/eTMR2_FLT1 (io), 18 PTE3/eTMR0_FLT0/SPI1_SIN/eTMR2_FLT0/SPI3_SOUT/TMU_IN6/ACMP0_OUT (io), 19 PTE12/eTMR0_FLT3/LINFlexD2_TX/eTMR5_FLT0/SPI3_PCS0 (io), 20 PTD17/eTMR0_FLT2/LINFlexD2_RX/eTMR5_FLT1 (io), 21 PTD16/EXTAL32/eTMR0_CH1/CAN4_TX/SPI0_SIN/ACMP0_ACTIVE/ETM_TRACE_D2/ETM_TRACE_CLKOUT (io), 22 PTD15/XTAL32/eTMR0_CH0/CAN4_RX/SPI0_SCK/ETM_TRACE_D3 (io), 23 PTE9/eTMR0_CH7/SPI1_SCK/I2C2_SDA (io), 24 PTD14/eTMR2_CH5/LINFlexD1_TX/SPI5_PCS3/SCU_CLKOUT (io), 25 PTD13/eTMR2_CH4/LINFlexD1_RX/SPI5_PCS2/RTC_CLKOUT (io), 26 PTE8/ACMP0_IN3/eTMR0_CH6/I2C2_SCL/SPI3_PCS1 (io), 27 PTB5/eTMR0_CH5/SPI0_PCS1/SPI0_PCS0/SCU_CLKOUT/TMU_IN0 (io), 28 PTB4/eTMR0_CH4/SPI0_SOUT/TMU_IN1 (io), 29 PTC3/ADC0_SE11/ACMP0_IN4/eTMR0_CH3/CAN0_TX/LINFlexD0_TX/SPI4_PCS0 (io), 30 PTC2/ADC0_SE10/ACMP0_IN5/eTMR0_CH2/CAN0_RX/LINFlexD0_RX/SPI4_SCK/ETM_TRACE_CLKOUT (io), 31 PTD7/ACMP0_IN6/LINFlexD2_TX/eTMR0_CH3/eTMR2_FLT3/SPI4_SIN/ETM_TRACE_D0 (io), 32 PTD6/ACMP0_IN7/LINFlexD2_RX/eTMR0_CH2/eTMR2_FLT2/SPI4_SOUT (io), 33 PTD5/eTMR2_CH3/lpTMR0_ALT2/eTMR2_FLT1/SPI4_PCS1/TMU_IN7 (io), 34 PTD12/eTMR2_CH2/ETM_TRACE_D1/SPI5_SIN (io), 35 PTD11/eTMR2_CH1/eTMR2_QD_PHA/ETM_TRACE_D2/SPI5_SOUT (io), 36 PTD10/eTMR2_CH0/eTMR2_QD_PHB/ETM_TRACE_D3/SPI5_SCK/SCU_CLKOUT (io), 37 VSS, 38 VDD, 39 PTC1/ADC0_SE9/eTMR0_CH1/SPI2_SOUT/CAN3_TX/eTMR1_CH7 (io), 40 PTC0/ADC0_SE8/eTMR0_CH0/SPI2_SIN/CAN3_RX/eTMR1_CH6 (io), 41 PTD9/LINFlexD4_TX/eTMR2_FLT3/eTMR1_CH5 (io), 42 PTD8/LINFlexD4_RX/eTMR2_FLT2/eTMR1_CH4 (io), 43 PTC17/ADC0_SE15/eTMR1_FLT3/CAN2_TX/SPI4_PCS0/eTMR2_CH1 (io), 44 PTC16/ADC0_SE14/eTMR1_FLT2/CAN2_RX/SPI4_SCK/eTMR2_CH0 (io), 45 PTC15/ADC0_SE13/eTMR1_CH3/SPI2_SCK/SPI4_SIN/LINFlexD4_TX/TMU_IN8 (io), 46 PTC14/ADC0_SE12/eTMR1_CH2/SPI2_PCS0/SPI4_SOUT/LINFlexD4_RX/TMU_IN9 (io), 47 PTB3/ADC0_SE7/eTMR1_CH1/SPI0_SIN/eTMR1_QD_PHA/TMU_IN2 (io), 48 PTB2/ADC0_SE6/eTMR1_CH0/SPI0_SCK/eTMR1_QD_PHB/TMU_IN3 (io), 49 PTC13/eTMR3_CH7/eTMR2_CH7 (io), 50 PTC12/eTMR3_CH6/eTMR2_CH6 (io), 51 PTC11/eTMR3_CH5/eTMR4_CH2/CAN5_TX/TMU_IN10 (io), 52 PTC10/eTMR3_CH4/CAN5_RX/TMU_IN11 (io), 53 PTB1/ADC0_SE5/ADC1_SE15/LINFlexD0_TX/SPI0_SOUT/TCLK_IN0/CAN0_TX/eTMR4_CH5 (io), 54 PTB0/ADC0_SE4/ADC1_SE14/LINFlexD0_RX/SPI0_PCS0/lpTMR0_ALT3/CAN0_RX/eTMR4_CH6 (io), 55 PTC9/LINFlexD1_TX/eTMR1_FLT1/eTMR5_CH0/CAN4_TX/SPI5_PCS1 (io), 56 PTC8/LINFlexD1_RX/eTMR1_FLT0/eTMR5_CH1/CAN4_RX/SPI5_PCS0 (io), 57 PTA7/ADC0_SE3/eTMR0_FLT2/eTMR5_CH3/RTC_CLKIN/I2C2_SCL/SPI5_SCK (io), 58 PTA6/ADC0_SE2/eTMR0_FLT1/SPI1_PCS1/eTMR5_CH5/I2C2_SDA/SPI5_SIN (io), 59 PTE7/eTMR0_CH7/eTMR3_FLT0/SPI5_SOUT (io), 60 VSS, 61 VDD, 62 PTA17/eTMR0_CH6/eTMR3_FLT0/EWDG_OUT_b/eTMR5_FLT0 (io), 63 PTB17/eTMR0_CH5/SPI1_PCS3/eTMR5_FLT1 (io), 64 PTB16/ADC1_SE15/eTMR0_CH4/SPI1_SOUT (io), 65 PTB15/ADC1_SE14/eTMR0_CH3/SPI1_SIN (io), 66 PTB14/ADC1_SE9/ADC0_SE9/eTMR0_CH2/SPI1_SCK (io), 67 PTB13/ADC1_SE8/ADC0_SE8/eTMR0_CH1/eTMR3_FLT1/CAN2_TX (io), 68 PTB12/ADC1_SE7/eTMR0_CH0/eTMR3_FLT2/CAN2_RX (io), 69 PTD4/ADC1_SE6/eTMR0_FLT3/eTMR3_FLT3/SPI5_PCS2 (io), 70 PTD3/ADC1_SE3/eTMR3_CH5/SPI1_PCS0/I2C1_SCL/CAN5_TX/TMU_IN4/NMI_b (io), 71 PTD2/ADC1_SE2/eTMR3_CH4/SPI1_SOUT/I2C1_SDA/CAN5_RX/TMU_IN5 (io), 72 PTA3/ADC1_SE1/eTMR3_CH1/I2C0_SCL/EWDG_IN/LINFlexD0_TX (io), 73 PTA2/ADC1_SE0/eTMR3_CH0/I2C0_SDA/EWDG_OUT_b/LINFlexD0_RX (io), 74 PTB11/eTMR3_CH3/LINFlexD5_TX (io), 75 PTB10/eTMR3_CH2/LINFlexD5_RX (io), 76 PTB9/eTMR3_CH1 (io), 77 PTB8/eTMR3_CH0 (io), 78 PTA1/ADC0_SE1/ACMP0_IN1/eTMR1_CH1/LINFlexD5_TX/eTMR1_QD_PHA/TMU_OUT0 (io), 79 PTA0/ADC0_SE0/ACMP0_IN0/eTMR2_CH1/LINFlexD5_RX/eTMR2_QD_PHA/TMU_OUT3 (io), 80 PTC7/ADC1_SE5/LINFlexD1_TX/CAN1_TX/eTMR3_CH3/eTMR1_QD_PHA (io), 81 PTC6/ADC1_SE4/LINFlexD1_RX/CAN1_RX/eTMR3_CH2/eTMR1_QD_PHB (io), 82 PTA16/ADC1_SE13/eTMR1_CH3/SPI1_PCS2 (io), 83 PTA15/ADC1_SE12/eTMR1_CH2/SPI0_PCS3/SPI2_PCS3 (io), 84 PTE6/ADC1_SE11/SPI0_PCS2/eTMR3_CH7/ETM_TRACE_D2/ETM_TRACE_CLKOUT (io), 85 PTE2/ADC1_SE10/SPI0_SOUT/lpTMR0_ALT3/eTMR3_CH6/ETM_TRACE_D3 (io), 86 VSS, 87 VDD, 88 PTA14/eTMR0_FLT0/eTMR3_FLT1/EWDG_IN/eTMR1_FLT0 (io), 89 PTA13/eTMR1_CH7/CAN1_TX/SPI3_PCS0/eTMR2_QD_PHA (io), 90 PTA12/eTMR1_CH6/CAN1_RX/SPI3_SCK/eTMR2_QD_PHB (io), 91 PTA11/eTMR1_CH5/SPI3_SIN/ACMP0_ACTIVE (io), 92 PTA10/eTMR1_CH4/SPI3_SOUT/JTAG_TDO_SWD_SWO (io), 93 PTE1/SPI0_SIN/SPI1_PCS0/eTMR1_FLT1 (io), 94 PTE0/SPI0_SCK/TCLK_IN1/SPI1_SOUT/eTMR1_FLT2 (io), 95 PTC5/eTMR2_CH0/RTC_CLKOUT/SPI3_PCS1/eTMR2_QD_PHB/JTAG_TDI (io), 96 PTC4/ACMP0_IN2/eTMR1_CH0/RTC_CLKOUT/EWDG_IN/eTMR1_QD_PHB/JTAG_TCK_SWD_CLK (io), 97 PTA5/CAN3_TX/TCLK_IN1/RESET_b (io), 98 PTA4/CAN3_RX/ACMP0_OUT/EWDG_OUT_b/JTAG_TMS_SWD_IO (io), 99 PTA9/LINFlexD2_TX/SPI2_PCS0/eTMR3_FLT2/eTMR1_FLT3/eTMR4_FLT0 (io), 100 PTA8/LINFlexD2_RX/SPI2_SOUT/eTMR3_FLT3/eTMR4_FLT1 (io)


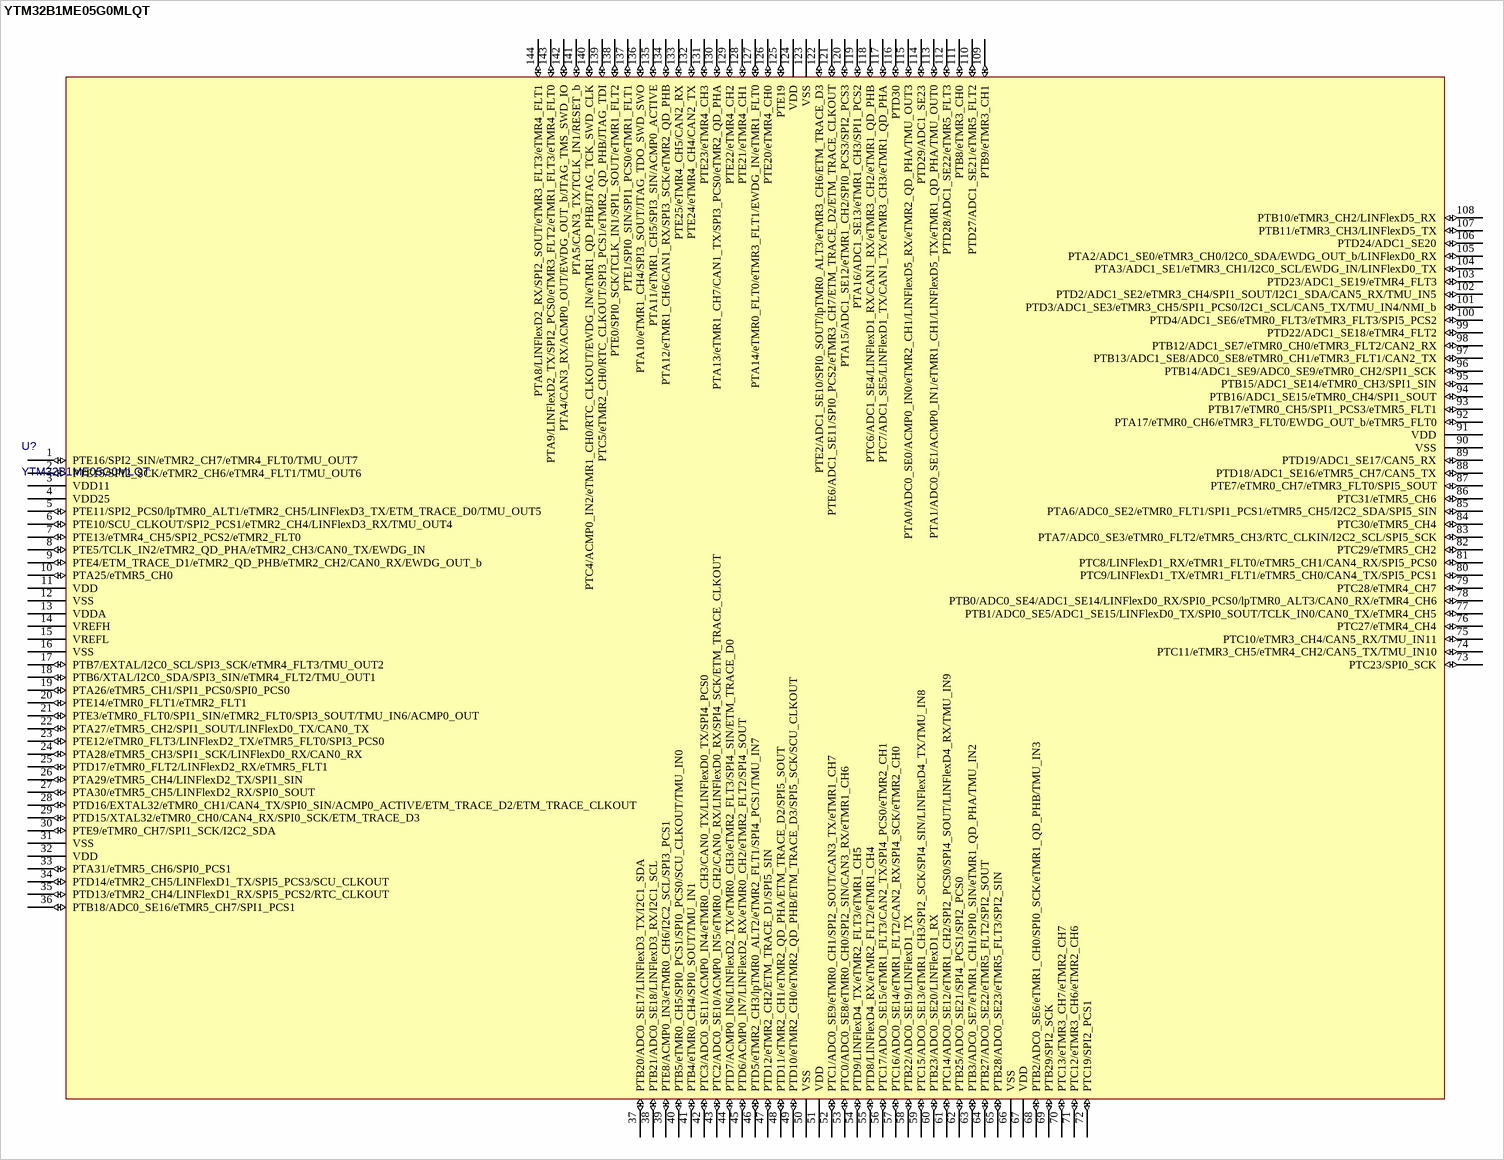
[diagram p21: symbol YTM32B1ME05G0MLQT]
## YTM32B1ME05G0MLQT
designator U?
B1M family  32-bit ARM Cortex-M33 MCU with 1M pflash, 256K dflash and 128K SRAM, LQFP-144 package
footprint LQFP144 (144-Pin Thin Quad Flat Pack 0.5 mm Pitch, IPC Medium Density)
pins: 1 PTE16/SPI2_SIN/eTMR2_CH7/eTMR4_FLT0/TMU_OUT7 (io), 2 PTE15/SPI2_SCK/eTMR2_CH6/eTMR4_FLT1/TMU_OUT6 (io), 3 VDD11, 4 VDD25, 5 PTE11/SPI2_PCS0/lpTMR0_ALT1/eTMR2_CH5/LINFlexD3_TX/ETM_TRACE_D0/TMU_OUT5 (io), 6 PTE10/SCU_CLKOUT/SPI2_PCS1/eTMR2_CH4/LINFlexD3_RX/TMU_OUT4 (io), 7 PTE13/eTMR4_CH5/SPI2_PCS2/eTMR2_FLT0 (io), 8 PTE5/TCLK_IN2/eTMR2_QD_PHA/eTMR2_CH3/CAN0_TX/EWDG_IN (io), 9 PTE4/ETM_TRACE_D1/eTMR2_QD_PHB/eTMR2_CH2/CAN0_RX/EWDG_OUT_b (io), 10 PTA25/eTMR5_CH0 (io), 11 VDD, 12 VSS, 13 VDDA, 14 VREFH, 15 VREFL, 16 VSS, 17 PTB7/EXTAL/I2C0_SCL/SPI3_SCK/eTMR4_FLT3/TMU_OUT2 (io), 18 PTB6/XTAL/I2C0_SDA/SPI3_SIN/eTMR4_FLT2/TMU_OUT1 (io), 19 PTA26/eTMR5_CH1/SPI1_PCS0/SPI0_PCS0 (io), 20 PTE14/eTMR0_FLT1/eTMR2_FLT1 (io), 21 PTE3/eTMR0_FLT0/SPI1_SIN/eTMR2_FLT0/SPI3_SOUT/TMU_IN6/ACMP0_OUT (io), 22 PTA27/eTMR5_CH2/SPI1_SOUT/LINFlexD0_TX/CAN0_TX (io), 23 PTE12/eTMR0_FLT3/LINFlexD2_TX/eTMR5_FLT0/SPI3_PCS0 (io), 24 PTA28/eTMR5_CH3/SPI1_SCK/LINFlexD0_RX/CAN0_RX (io), 25 PTD17/eTMR0_FLT2/LINFlexD2_RX/eTMR5_FLT1 (io), 26 PTA29/eTMR5_CH4/LINFlexD2_TX/SPI1_SIN (io), 27 PTA30/eTMR5_CH5/LINFlexD2_RX/SPI0_SOUT (io), 28 PTD16/EXTAL32/eTMR0_CH1/CAN4_TX/SPI0_SIN/ACMP0_ACTIVE/ETM_TRACE_D2/ETM_TRACE_CLKOUT (io), 29 PTD15/XTAL32/eTMR0_CH0/CAN4_RX/SPI0_SCK/ETM_TRACE_D3 (io), 30 PTE9/eTMR0_CH7/SPI1_SCK/I2C2_SDA (io), 31 VSS, 32 VDD, 33 PTA31/eTMR5_CH6/SPI0_PCS1 (io), 34 PTD14/eTMR2_CH5/LINFlexD1_TX/SPI5_PCS3/SCU_CLKOUT (io), 35 PTD13/eTMR2_CH4/LINFlexD1_RX/SPI5_PCS2/RTC_CLKOUT (io), 36 PTB18/ADC0_SE16/eTMR5_CH7/SPI1_PCS1 (io), 37 PTB20/ADC0_SE17/LINFlexD3_TX/I2C1_SDA (io), 38 PTB21/ADC0_SE18/LINFlexD3_RX/I2C1_SCL (io), 39 PTE8/ACMP0_IN3/eTMR0_CH6/I2C2_SCL/SPI3_PCS1 (io), 40 PTB5/eTMR0_CH5/SPI0_PCS1/SPI0_PCS0/SCU_CLKOUT/TMU_IN0 (io), 41 PTB4/eTMR0_CH4/SPI0_SOUT/TMU_IN1 (io), 42 PTC3/ADC0_SE11/ACMP0_IN4/eTMR0_CH3/CAN0_TX/LINFlexD0_TX/SPI4_PCS0 (io), 43 PTC2/ADC0_SE10/ACMP0_IN5/eTMR0_CH2/CAN0_RX/LINFlexD0_RX/SPI4_SCK/ETM_TRACE_CLKOUT (io), 44 PTD7/ACMP0_IN6/LINFlexD2_TX/eTMR0_CH3/eTMR2_FLT3/SPI4_SIN/ETM_TRACE_D0 (io), 45 PTD6/ACMP0_IN7/LINFlexD2_RX/eTMR0_CH2/eTMR2_FLT2/SPI4_SOUT (io), 46 PTD5/eTMR2_CH3/lpTMR0_ALT2/eTMR2_FLT1/SPI4_PCS1/TMU_IN7 (io), 47 PTD12/eTMR2_CH2/ETM_TRACE_D1/SPI5_SIN (io), 48 PTD11/eTMR2_CH1/eTMR2_QD_PHA/ETM_TRACE_D2/SPI5_SOUT (io), 49 PTD10/eTMR2_CH0/eTMR2_QD_PHB/ETM_TRACE_D3/SPI5_SCK/SCU_CLKOUT (io), 50 VSS, 51 VDD, 52 PTC1/ADC0_SE9/eTMR0_CH1/SPI2_SOUT/CAN3_TX/eTMR1_CH7 (io), 53 PTC0/ADC0_SE8/eTMR0_CH0/SPI2_SIN/CAN3_RX/eTMR1_CH6 (io), 54 PTD9/LINFlexD4_TX/eTMR2_FLT3/eTMR1_CH5 (io), 55 PTD8/LINFlexD4_RX/eTMR2_FLT2/eTMR1_CH4 (io), 56 PTC17/ADC0_SE15/eTMR1_FLT3/CAN2_TX/SPI4_PCS0/eTMR2_CH1 (io), 57 PTC16/ADC0_SE14/eTMR1_FLT2/CAN2_RX/SPI4_SCK/eTMR2_CH0 (io), 58 PTB22/ADC0_SE19/LINFlexD1_TX (io), 59 PTC15/ADC0_SE13/eTMR1_CH3/SPI2_SCK/SPI4_SIN/LINFlexD4_TX/TMU_IN8 (io), 60 PTB23/ADC0_SE20/LINFlexD1_RX (io), 61 PTC14/ADC0_SE12/eTMR1_CH2/SPI2_PCS0/SPI4_SOUT/LINFlexD4_RX/TMU_IN9 (io), 62 PTB25/ADC0_SE21/SPI4_PCS1/SPI2_PCS0 (io), 63 PTB3/ADC0_SE7/eTMR1_CH1/SPI0_SIN/eTMR1_QD_PHA/TMU_IN2 (io), 64 PTB27/ADC0_SE22/eTMR5_FLT2/SPI2_SOUT (io), 65 PTB28/ADC0_SE23/eTMR5_FLT3/SPI2_SIN (io), 66 VSS, 67 VDD, 68 PTB2/ADC0_SE6/eTMR1_CH0/SPI0_SCK/eTMR1_QD_PHB/TMU_IN3 (io), 69 PTB29/SPI2_SCK (io), 70 PTC13/eTMR3_CH7/eTMR2_CH7 (io), 71 PTC12/eTMR3_CH6/eTMR2_CH6 (io), 72 PTC19/SPI2_PCS1 (io), 73 PTC23/SPI0_SCK (io), 74 PTC11/eTMR3_CH5/eTMR4_CH2/CAN5_TX/TMU_IN10 (io), 75 PTC10/eTMR3_CH4/CAN5_RX/TMU_IN11 (io), 76 PTC27/eTMR4_CH4 (io), 77 PTB1/ADC0_SE5/ADC1_SE15/LINFlexD0_TX/SPI0_SOUT/TCLK_IN0/CAN0_TX/eTMR4_CH5 (io), 78 PTB0/ADC0_SE4/ADC1_SE14/LINFlexD0_RX/SPI0_PCS0/lpTMR0_ALT3/CAN0_RX/eTMR4_CH6 (io), 79 PTC28/eTMR4_CH7 (io), 80 PTC9/LINFlexD1_TX/eTMR1_FLT1/eTMR5_CH0/CAN4_TX/SPI5_PCS1 (io), 81 PTC8/LINFlexD1_RX/eTMR1_FLT0/eTMR5_CH1/CAN4_RX/SPI5_PCS0 (io), 82 PTC29/eTMR5_CH2 (io), 83 PTA7/ADC0_SE3/eTMR0_FLT2/eTMR5_CH3/RTC_CLKIN/I2C2_SCL/SPI5_SCK (io), 84 PTC30/eTMR5_CH4 (io), 85 PTA6/ADC0_SE2/eTMR0_FLT1/SPI1_PCS1/eTMR5_CH5/I2C2_SDA/SPI5_SIN (io), 86 PTC31/eTMR5_CH6 (io), 87 PTE7/eTMR0_CH7/eTMR3_FLT0/SPI5_SOUT (io), 88 PTD18/ADC1_SE16/eTMR5_CH7/CAN5_TX (io), 89 PTD19/ADC1_SE17/CAN5_RX (io), 90 VSS, 91 VDD, 92 PTA17/eTMR0_CH6/eTMR3_FLT0/EWDG_OUT_b/eTMR5_FLT0 (io), 93 PTB17/eTMR0_CH5/SPI1_PCS3/eTMR5_FLT1 (io), 94 PTB16/ADC1_SE15/eTMR0_CH4/SPI1_SOUT (io), 95 PTB15/ADC1_SE14/eTMR0_CH3/SPI1_SIN (io), 96 PTB14/ADC1_SE9/ADC0_SE9/eTMR0_CH2/SPI1_SCK (io), 97 PTB13/ADC1_SE8/ADC0_SE8/eTMR0_CH1/eTMR3_FLT1/CAN2_TX (io), 98 PTB12/ADC1_SE7/eTMR0_CH0/eTMR3_FLT2/CAN2_RX (io), 99 PTD22/ADC1_SE18/eTMR4_FLT2 (io), 100 PTD4/ADC1_SE6/eTMR0_FLT3/eTMR3_FLT3/SPI5_PCS2 (io), 101 PTD3/ADC1_SE3/eTMR3_CH5/SPI1_PCS0/I2C1_SCL/CAN5_TX/TMU_IN4/NMI_b (io), 102 PTD2/ADC1_SE2/eTMR3_CH4/SPI1_SOUT/I2C1_SDA/CAN5_RX/TMU_IN5 (io), 103 PTD23/ADC1_SE19/eTMR4_FLT3 (io), 104 PTA3/ADC1_SE1/eTMR3_CH1/I2C0_SCL/EWDG_IN/LINFlexD0_TX (io), 105 PTA2/ADC1_SE0/eTMR3_CH0/I2C0_SDA/EWDG_OUT_b/LINFlexD0_RX (io), 106 PTD24/ADC1_SE20 (io), 107 PTB11/eTMR3_CH3/LINFlexD5_TX (io), 108 PTB10/eTMR3_CH2/LINFlexD5_RX (io), 109 PTB9/eTMR3_CH1 (io), 110 PTD27/ADC1_SE21/eTMR5_FLT2 (io), 111 PTB8/eTMR3_CH0 (io), 112 PTD28/ADC1_SE22/eTMR5_FLT3 (io), 113 PTA1/ADC0_SE1/ACMP0_IN1/eTMR1_CH1/LINFlexD5_TX/eTMR1_QD_PHA/TMU_OUT0 (io), 114 PTD29/ADC1_SE23 (io), 115 PTA0/ADC0_SE0/ACMP0_IN0/eTMR2_CH1/LINFlexD5_RX/eTMR2_QD_PHA/TMU_OUT3 (io), 116 PTD30 (io), 117 PTC7/ADC1_SE5/LINFlexD1_TX/CAN1_TX/eTMR3_CH3/eTMR1_QD_PHA (io), 118 PTC6/ADC1_SE4/LINFlexD1_RX/CAN1_RX/eTMR3_CH2/eTMR1_QD_PHB (io), 119 PTA16/ADC1_SE13/eTMR1_CH3/SPI1_PCS2 (io), 120 PTA15/ADC1_SE12/eTMR1_CH2/SPI0_PCS3/SPI2_PCS3 (io), 121 PTE6/ADC1_SE11/SPI0_PCS2/eTMR3_CH7/ETM_TRACE_D2/ETM_TRACE_CLKOUT (io), 122 PTE2/ADC1_SE10/SPI0_SOUT/lpTMR0_ALT3/eTMR3_CH6/ETM_TRACE_D3 (io), 123 VSS, 124 VDD, 125 PTE19 (io), 126 PTE20/eTMR4_CH0 (io), 127 PTA14/eTMR0_FLT0/eTMR3_FLT1/EWDG_IN/eTMR1_FLT0 (io), 128 PTE21/eTMR4_CH1 (io), 129 PTE22/eTMR4_CH2 (io), 130 PTA13/eTMR1_CH7/CAN1_TX/SPI3_PCS0/eTMR2_QD_PHA (io), 131 PTE23/eTMR4_CH3 (io), 132 PTE24/eTMR4_CH4/CAN2_TX (io), 133 PTE25/eTMR4_CH5/CAN2_RX (io), 134 PTA12/eTMR1_CH6/CAN1_RX/SPI3_SCK/eTMR2_QD_PHB (io), 135 PTA11/eTMR1_CH5/SPI3_SIN/ACMP0_ACTIVE (io), 136 PTA10/eTMR1_CH4/SPI3_SOUT/JTAG_TDO_SWD_SWO (io), 137 PTE1/SPI0_SIN/SPI1_PCS0/eTMR1_FLT1 (io), 138 PTE0/SPI0_SCK/TCLK_IN1/SPI1_SOUT/eTMR1_FLT2 (io), 139 PTC5/eTMR2_CH0/RTC_CLKOUT/SPI3_PCS1/eTMR2_QD_PHB/JTAG_TDI (io), 140 PTC4/ACMP0_IN2/eTMR1_CH0/RTC_CLKOUT/EWDG_IN/eTMR1_QD_PHB/JTAG_TCK_SWD_CLK (io), 141 PTA5/CAN3_TX/TCLK_IN1/RESET_b (io), 142 PTA4/CAN3_RX/ACMP0_OUT/EWDG_OUT_b/JTAG_TMS_SWD_IO (io), 143 PTA9/LINFlexD2_TX/SPI2_PCS0/eTMR3_FLT2/eTMR1_FLT3/eTMR4_FLT0 (io), 144 PTA8/LINFlexD2_RX/SPI2_SOUT/eTMR3_FLT3/eTMR4_FLT1 (io)


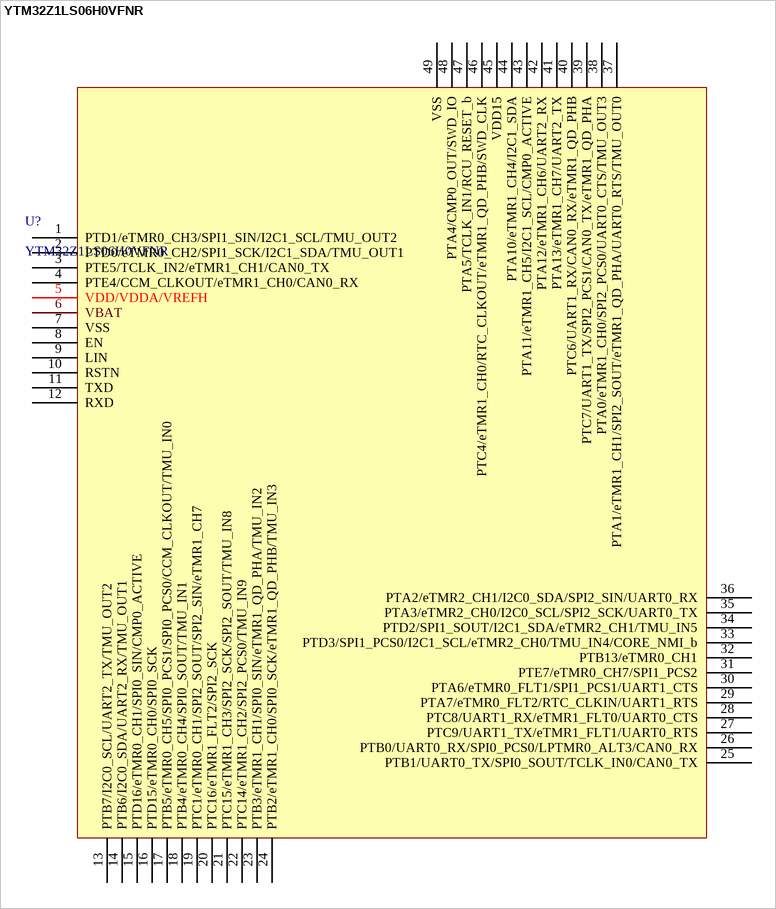
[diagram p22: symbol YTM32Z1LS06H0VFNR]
## YTM32Z1LS06H0VFNR
designator U?
Z1L family  32-bit ARM Cortex-M33 MCU With 12V LDO and LIN transceiver, 128K flash and 16K SRAM, QFN-48 package
footprint QFN48 (QFN, 48-Leads, Body 7.1x7.1mm, Pitch 0.5mm, Thermal Pad 5.6x5.6mm, IPC Low Density)
pins: 1 PTD1/eTMR0_CH3/SPI1_SIN/I2C1_SCL/TMU_OUT2, 2 PTD0/eTMR0_CH2/SPI1_SCK/I2C1_SDA/TMU_OUT1, 3 PTE5/TCLK_IN2/eTMR1_CH1/CAN0_TX, 4 PTE4/CCM_CLKOUT/eTMR1_CH0/CAN0_RX, 5 VDD/VDDA/VREFH, 6 VBAT, 7 VSS, 8 EN, 9 LIN, 10 RSTN, 11 TXD, 12 RXD, 13 PTB7/I2C0_SCL/UART2_TX/TMU_OUT2, 14 PTB6/I2C0_SDA/UART2_RX/TMU_OUT1, 15 PTD16/eTMR0_CH1/SPI0_SIN/CMP0_ACTIVE, 16 PTD15/eTMR0_CH0/SPI0_SCK, 17 PTB5/eTMR0_CH5/SPI0_PCS1/SPI0_PCS0/CCM_CLKOUT/TMU_IN0, 18 PTB4/eTMR0_CH4/SPI0_SOUT/TMU_IN1, 19 PTC1/eTMR0_CH1/SPI2_SOUT/SPI2_SIN/eTMR1_CH7, 20 PTC16/eTMR1_FLT2/SPI2_SCK, 21 PTC15/eTMR1_CH3/SPI2_SCK/SPI2_SOUT/TMU_IN8, 22 PTC14/eTMR1_CH2/SPI2_PCS0/TMU_IN9, 23 PTB3/eTMR1_CH1/SPI0_SIN/eTMR1_QD_PHA/TMU_IN2, 24 PTB2/eTMR1_CH0/SPI0_SCK/eTMR1_QD_PHB/TMU_IN3, 25 PTB1/UART0_TX/SPI0_SOUT/TCLK_IN0/CAN0_TX, 26 PTB0/UART0_RX/SPI0_PCS0/LPTMR0_ALT3/CAN0_RX, 27 PTC9/UART1_TX/eTMR1_FLT1/UART0_RTS, 28 PTC8/UART1_RX/eTMR1_FLT0/UART0_CTS, 29 PTA7/eTMR0_FLT2/RTC_CLKIN/UART1_RTS, 30 PTA6/eTMR0_FLT1/SPI1_PCS1/UART1_CTS, 31 PTE7/eTMR0_CH7/SPI1_PCS2, 32 PTB13/eTMR0_CH1, 33 PTD3/SPI1_PCS0/I2C1_SCL/eTMR2_CH0/TMU_IN4/CORE_NMI_b, 34 PTD2/SPI1_SOUT/I2C1_SDA/eTMR2_CH1/TMU_IN5, 35 PTA3/eTMR2_CH0/I2C0_SCL/SPI2_SCK/UART0_TX, 36 PTA2/eTMR2_CH1/I2C0_SDA/SPI2_SIN/UART0_RX, 37 PTA1/eTMR1_CH1/SPI2_SOUT/eTMR1_QD_PHA/UART0_RTS/TMU_OUT0, 38 PTA0/eTMR1_CH0/SPI2_PCS0/UART0_CTS/TMU_OUT3, 39 PTC7/UART1_TX/SPI2_PCS1/CAN0_TX/eTMR1_QD_PHA, 40 PTC6/UART1_RX/CAN0_RX/eTMR1_QD_PHB, 41 PTA13/eTMR1_CH7/UART2_TX, 42 PTA12/eTMR1_CH6/UART2_RX, 43 PTA11/eTMR1_CH5/I2C1_SCL/CMP0_ACTIVE, 44 PTA10/eTMR1_CH4/I2C1_SDA, 45 VDD15, 46 PTC4/eTMR1_CH0/RTC_CLKOUT/eTMR1_QD_PHB/SWD_CLK, 47 PTA5/TCLK_IN1/RCU_RESET_b, 48 PTA4/CMP0_OUT/SWD_IO, 49 VSS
